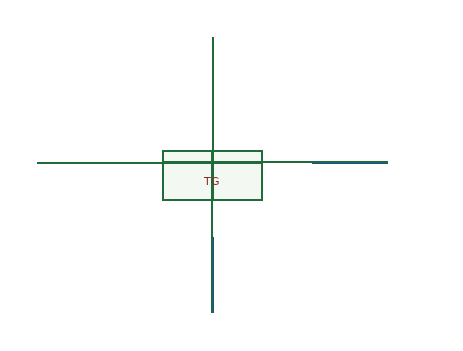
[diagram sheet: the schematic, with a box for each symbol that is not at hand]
v {xschem version=2.9.9 file_version=1.2 }
G {}
K {}
V {}
S {}
E {}
N -80 -60 -20 -60 { lab=#net1}
N 140 -60 200 -60 { lab=#net2}
N 60 -160 60 -120 { lab=#net3}
N 60 -0 60 60 { lab=#net4}
C {MISC/TG/TG.sym} 0 0 0 0 {}
